### Tool : gds2rh
### RedHawk Version : 19.1.7p1 RHEL6
### Vendor : Apache Design, Inc. A Subsidiary of ANSYS, Inc. 
### Date : Mar 02 2019 00:03:14 

### Date generated : Wed Sep 14 16:24:09 2022
 
### Command : gds2rh /nfs/an/disks/an_mos_scratch01/mos/prod/runs/c224uhdlpsprf-ext-version-r1-0-1/r641703_00_00/r641703_00_00/avm/rv_avm/gds2rh_options_powerup.txt

VERSION 5.5 ;
NAMESCASESENSITIVE ON ;
DIVIDERCHAR "/" ;
BUSBITCHARS "[]" ;
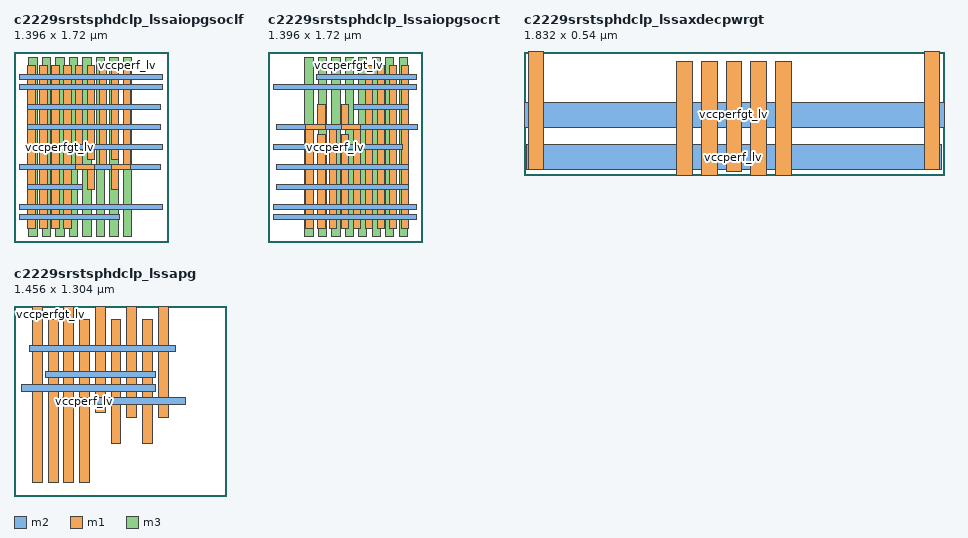
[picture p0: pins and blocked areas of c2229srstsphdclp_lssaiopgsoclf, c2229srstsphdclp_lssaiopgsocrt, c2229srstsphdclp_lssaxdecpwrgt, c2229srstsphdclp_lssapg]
MACRO c2229srstsphdclp_lssaiopgsoclf 
 ORIGIN 0.0000 0.0000 ; 
 SIZE 1.396000 BY 1.720000 ;
 PIN pwrenin_b
  DIRECTION INOUT ;
  USE SIGNAL ;
  PORT
  END
 END pwrenin_b
 PIN vccperf_lv
  DIRECTION INOUT ;
  USE POWER ;
  PORT
   LAYER m2 ;
   RECT 0.047000 0.658000 1.322000 0.702000 ;
   RECT 0.050000 0.298000 1.346000 0.342000 ;
   RECT 0.050000 1.378000 1.346000 1.422000 ;
   LAYER m1 ;
   RECT 0.124000 0.118000 0.192000 1.602000 ;
   RECT 0.340000 0.118000 0.408000 1.602000 ;
   RECT 0.556000 0.658000 0.732000 0.702000 ;
   RECT 0.556000 0.702000 0.624000 1.602000 ;
   RECT 0.664000 0.478000 0.732000 0.658000 ;
   RECT 0.772000 0.658000 0.840000 1.602000 ;
   RECT 0.880000 0.478000 0.948000 0.658000 ;
   RECT 0.880000 0.658000 1.056000 0.702000 ;
   RECT 0.988000 0.702000 1.056000 1.602000 ;
   LAYER m3 ;
   RECT 0.256000 0.050000 0.332000 1.670000 ;
   RECT 0.500000 0.050000 0.576000 1.670000 ;
   RECT 0.744000 0.050000 0.820000 1.670000 ;
   RECT 0.988000 0.050000 1.064000 1.670000 ;
  END
 END vccperf_lv
 PIN vccperfgt_lv
  DIRECTION INOUT ;
  USE POWER ;
  PORT
   LAYER m2 ;
   RECT 0.050000 0.208000 0.954000 0.252000 ;
   RECT 0.050000 1.468000 1.346000 1.512000 ;
   RECT 0.122000 0.478000 0.618500 0.522000 ;
   RECT 0.122000 1.018000 1.322000 1.062000 ;
   RECT 0.122000 1.198000 1.322000 1.242000 ;
   RECT 0.182000 0.838000 1.346000 0.882000 ;
   LAYER m3 ;
   RECT 0.134000 0.050000 0.210000 1.670000 ;
   RECT 0.378000 0.050000 0.454000 1.670000 ;
   RECT 0.622000 0.050000 0.698000 1.670000 ;
   RECT 0.866000 0.050000 0.942000 1.670000 ;
   LAYER m1 ;
   RECT 0.232000 0.118000 0.300000 1.602000 ;
   RECT 0.448000 0.118000 0.516000 1.602000 ;
   RECT 0.664000 0.748000 0.732000 1.602000 ;
   RECT 0.880000 0.748000 0.948000 1.602000 ;
  END
 END vccperfgt_lv
END c2229srstsphdclp_lssaiopgsoclf
MACRO c2229srstsphdclp_lssaiopgsocrt 
 ORIGIN 0.0000 0.0000 ; 
 SIZE 1.396000 BY 1.720000 ;
 PIN pwrenin_b
  DIRECTION INOUT ;
  USE SIGNAL ;
  PORT
  END
 END pwrenin_b
 PIN vccperf_lv
  DIRECTION INOUT ;
  USE POWER ;
  PORT
   LAYER m2 ;
   RECT 0.050000 0.298000 1.346000 0.342000 ;
   RECT 0.050000 1.378000 1.346000 1.422000 ;
   RECT 0.074000 1.018000 1.349000 1.062000 ;
   LAYER m3 ;
   RECT 0.332000 0.050000 0.408000 1.670000 ;
   RECT 0.576000 0.050000 0.652000 1.670000 ;
   RECT 0.820000 0.050000 0.896000 1.670000 ;
   RECT 1.064000 0.050000 1.140000 1.670000 ;
   LAYER m1 ;
   RECT 0.340000 0.118000 0.408000 1.018000 ;
   RECT 0.340000 1.018000 0.516000 1.062000 ;
   RECT 0.448000 1.062000 0.516000 1.242000 ;
   RECT 0.556000 0.118000 0.624000 1.062000 ;
   RECT 0.664000 1.018000 0.840000 1.062000 ;
   RECT 0.664000 1.062000 0.732000 1.242000 ;
   RECT 0.772000 0.118000 0.840000 1.018000 ;
   RECT 0.988000 0.118000 1.056000 1.602000 ;
   RECT 1.204000 0.118000 1.272000 1.602000 ;
  END
 END vccperf_lv
 PIN vccperfgt_lv
  DIRECTION INOUT ;
  USE POWER ;
  PORT
   LAYER m2 ;
   RECT 0.050000 0.208000 1.346000 0.252000 ;
   RECT 0.050000 0.838000 1.214000 0.882000 ;
   RECT 0.074000 0.478000 1.274000 0.522000 ;
   RECT 0.074000 0.658000 1.274000 0.702000 ;
   RECT 0.442000 1.468000 1.346000 1.512000 ;
   RECT 0.777500 1.198000 1.274000 1.242000 ;
   LAYER m1 ;
   RECT 0.448000 0.118000 0.516000 0.972000 ;
   RECT 0.664000 0.118000 0.732000 0.972000 ;
   RECT 0.880000 0.118000 0.948000 1.602000 ;
   RECT 1.096000 0.118000 1.164000 1.602000 ;
   LAYER m3 ;
   RECT 0.454000 0.050000 0.530000 1.670000 ;
   RECT 0.698000 0.050000 0.774000 1.670000 ;
   RECT 0.942000 0.050000 1.018000 1.670000 ;
   RECT 1.186000 0.050000 1.262000 1.670000 ;
  END
 END vccperfgt_lv
END c2229srstsphdclp_lssaiopgsocrt
MACRO c2229srstsphdclp_lssaxdecpwrgt 
 ORIGIN 0.0000 0.0000 ; 
 SIZE 1.832000 BY 0.540000 ;
 PIN pwrenin_b
  DIRECTION INOUT ;
  USE SIGNAL ;
  PORT
  END
 END pwrenin_b
 PIN vccperf_lv
  DIRECTION INOUT ;
  USE POWER ;
  PORT
   LAYER m2 ;
   RECT 0.011500 0.024000 1.820000 0.132000 ;
   LAYER m1 ;
   RECT 0.666000 0.000000 0.734000 0.494000 ;
   RECT 0.882000 0.014000 0.950000 0.494000 ;
   RECT 1.098000 0.000000 1.166000 0.494000 ;
  END
 END vccperf_lv
 PIN vccperfgt_lv
  DIRECTION INOUT ;
  USE POWER ;
  PORT
   LAYER m2 ;
   RECT 0.000000 0.208000 1.832000 0.316000 ;
   LAYER m1 ;
   RECT 0.018000 0.022000 0.086000 0.540000 ;
   RECT 0.774000 0.000000 0.842000 0.494000 ;
   RECT 0.990000 0.000000 1.058000 0.494000 ;
   RECT 1.746000 0.022000 1.814000 0.540000 ;
  END
 END vccperfgt_lv
END c2229srstsphdclp_lssaxdecpwrgt
MACRO c2229srstsphdclp_lssapg 
 ORIGIN 0.0000 0.0000 ; 
 SIZE 1.456000 BY 1.304000 ;
 PIN pwrenin_b
  DIRECTION INOUT ;
  USE SIGNAL ;
  PORT
  END
 END pwrenin_b
 PIN vccperf_lv
  DIRECTION INOUT ;
  USE POWER ;
  PORT
   LAYER m2 ;
   RECT 0.052000 0.720000 0.968000 0.764000 ;
   RECT 0.216000 0.810000 0.968000 0.854000 ;
   LAYER m1 ;
   RECT 0.234000 0.090000 0.302000 1.214000 ;
   RECT 0.450000 0.090000 0.518000 1.214000 ;
   RECT 0.666000 0.360000 0.734000 1.214000 ;
   RECT 0.882000 0.360000 0.950000 1.214000 ;
  END
 END vccperf_lv
 PIN vccperfgt_lv
  DIRECTION INOUT ;
  USE POWER ;
  PORT
   LAYER m2 ;
   RECT 0.108000 0.990000 1.108000 1.034000 ;
   RECT 0.324000 0.630000 1.179000 0.674000 ;
   LAYER m1 ;
   RECT 0.126000 0.090000 0.194000 1.304000 ;
   RECT 0.342000 0.090000 0.410000 1.304000 ;
   RECT 0.558000 0.572000 0.626000 1.304000 ;
   RECT 0.774000 0.540000 0.842000 1.304000 ;
   RECT 0.990000 0.540000 1.058000 1.304000 ;
  END
 END vccperfgt_lv
END c2229srstsphdclp_lssapg
END LIBRARY
